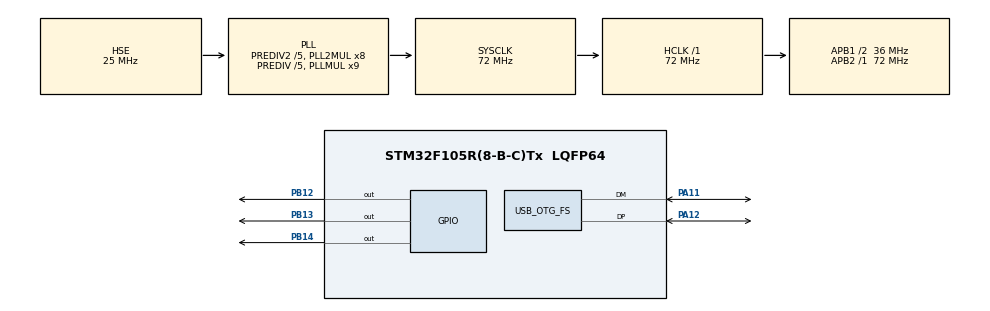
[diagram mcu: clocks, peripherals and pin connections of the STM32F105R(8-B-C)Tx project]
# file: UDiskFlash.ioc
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Mcu.Family=STM32F1
Mcu.Name=STM32F105R(8-B-C)Tx
Mcu.Package=LQFP64
NVIC.OTG_FS_IRQn=true\:1\:0\:true\:false\:true\:true\:true
NVIC.PriorityGroup=NVIC_PRIORITYGROUP_4
PA11.Mode=Device_Only
PA11.Signal=USB_OTG_FS_DM
PA12.Mode=Device_Only
PA12.Signal=USB_OTG_FS_DP
PB12.Signal=GPIO_Output
PB13.Signal=GPIO_Output
PB14.Signal=GPIO_Output
PD0-OSC_IN.Mode=HSE-External-Oscillator
PD0-OSC_IN.Signal=RCC_OSC_IN
PD1-OSC_OUT.Mode=HSE-External-Oscillator
PD1-OSC_OUT.Signal=RCC_OSC_OUT
ProjectManager.HeapSize=0x800
ProjectManager.StackSize=0x1000
ProjectManager.TargetToolchain=MDK-ARM V5
RCC.AHBFreq_Value=72000000
RCC.APB1CLKDivider=RCC_HCLK_DIV2
RCC.APB1Freq_Value=36000000
RCC.APB1TimFreq_Value=72000000
RCC.APB2Freq_Value=72000000
RCC.APB2TimFreq_Value=72000000
RCC.HCLKFreq_Value=72000000
RCC.HSEDivPLL=RCC_HSE_PREDIV_DIV5
RCC.HSE_VALUE=25000000
RCC.PLLMUL=RCC_PLL_MUL9
RCC.Prediv1Source=RCC_PREDIV1_SOURCE_PLL2
RCC.Prediv2=RCC_HSE_PREDIV2_DIV5
RCC.SYSCLKFreq_VALUE=72000000
RCC.SYSCLKSource=RCC_SYSCLKSOURCE_PLLCLK
RCC.USBFreq_Value=48000000
USB_DEVICE.CLASS_NAME_FS=MSC
USB_DEVICE.MANUFACTURER_STRING=ShareLink
USB_DEVICE.PRODUCT_STRING_MSC_FS=XL Mass Storage
USB_DEVICE.VirtualMode=Msc
USB_DEVICE.VirtualModeFS=Msc_FS
USB_OTG_FS.VirtualMode=Device_Only
VP_SYS_VS_ND.Mode=No_Debug
VP_USB_DEVICE_VS_USB_DEVICE_MSC_FS.Mode=MSC_FS
board=custom

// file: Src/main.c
/* USER CODE BEGIN Header */
/**
  ******************************************************************************
  * @file           : main.c
  * @brief          : Main program body
  ******************************************************************************
  * @attention
  *
  * <h2><center>&copy; Copyright (c) 2019 STMicroelectronics.
  * All rights reserved.</center></h2>
  *
  * This software component is licensed by ST under Ultimate Liberty license
  * SLA0044, the "License"; You may not use this file except in compliance with
  * the License. You may obtain a copy of the License at:
  *                             www.st.com/SLA0044
  *
  ******************************************************************************
  */
/* USER CODE END Header */

#include "main.h"
#include "usb_device.h"

/* USER CODE BEGIN PV */
typedef  void (*pFunction)(void);
uint32_t JumpAddress;
pFunction Jump_To_Application;

/* USER CODE END PV */

void SystemClock_Config(void);
static void MX_GPIO_Init(void);

int main(void)
{
	/* USER CODE BEGIN 1 */
	uint32_t i=0;

  /* USER CODE END 1 */

  /* MCU Configuration--------------------------------------------------------*/
  /* Reset of all peripherals, Initializes the Flash interface and the Systick. */
  HAL_Init();
  /* Configure the system clock */
  SystemClock_Config();
  /* USER CODE BEGIN SysInit */
	MX_GPIO_Init();
	/* USER CODE END SysInit */
	if(!HAL_GPIO_ReadPin(GPIOB, GPIO_PIN_4)){
		HAL_GPIO_WritePin(GPIOB, GPIO_PIN_12,GPIO_PIN_RESET);	//SYS_LED_ON
		/* Initialize all configured peripherals */
		MX_USB_DEVICE_Init();
		while(1);
	}

	/* USER CODE BEGIN 2 */
	__set_PRIMASK(1);
	if(((*(__IO uint32_t *) ApplicationAddress) & 0x2FFE0000) == 0x20000000)
	{
    HAL_DeInit();
		JumpAddress = *(__IO uint32_t *) (ApplicationAddress + 4);
		Jump_To_Application = (pFunction) JumpAddress;

		__set_MSP(*(__IO uint32_t *) ApplicationAddress);
		Jump_To_Application();
	}

  /* USER CODE END 2 */

  /* Infinite loop */
  while (1)
  {
		Error_Handler();
  }
}

void SystemClock_Config(void)
{
  RCC_OscInitTypeDef RCC_OscInitStruct = {0};
  RCC_ClkInitTypeDef RCC_ClkInitStruct = {0};
  RCC_PeriphCLKInitTypeDef PeriphClkInit = {0};

  /** Initializes the CPU, AHB and APB busses clocks
  */
  RCC_OscInitStruct.OscillatorType = RCC_OSCILLATORTYPE_HSE;
  RCC_OscInitStruct.HSEState = RCC_HSE_ON;
  RCC_OscInitStruct.HSEPredivValue = RCC_HSE_PREDIV_DIV5;
  RCC_OscInitStruct.HSIState = RCC_HSI_ON;
  RCC_OscInitStruct.Prediv1Source = RCC_PREDIV1_SOURCE_PLL2;
  RCC_OscInitStruct.PLL.PLLState = RCC_PLL_ON;
  RCC_OscInitStruct.PLL.PLLSource = RCC_PLLSOURCE_HSE;
  RCC_OscInitStruct.PLL.PLLMUL = RCC_PLL_MUL9;
  RCC_OscInitStruct.PLL2.PLL2State = RCC_PLL2_ON;
  RCC_OscInitStruct.PLL2.PLL2MUL = RCC_PLL2_MUL8;
  RCC_OscInitStruct.PLL2.HSEPrediv2Value = RCC_HSE_PREDIV2_DIV5;
  if (HAL_RCC_OscConfig(&RCC_OscInitStruct) != HAL_OK)
  {
    Error_Handler();
  }
  /** Initializes the CPU, AHB and APB busses clocks
  */
  RCC_ClkInitStruct.ClockType = RCC_CLOCKTYPE_HCLK|RCC_CLOCKTYPE_SYSCLK
                              |RCC_CLOCKTYPE_PCLK1|RCC_CLOCKTYPE_PCLK2;
  RCC_ClkInitStruct.SYSCLKSource = RCC_SYSCLKSOURCE_PLLCLK;
  RCC_ClkInitStruct.AHBCLKDivider = RCC_SYSCLK_DIV1;
  RCC_ClkInitStruct.APB1CLKDivider = RCC_HCLK_DIV2;
  RCC_ClkInitStruct.APB2CLKDivider = RCC_HCLK_DIV1;

  if (HAL_RCC_ClockConfig(&RCC_ClkInitStruct, FLASH_LATENCY_2) != HAL_OK)
  {
    Error_Handler();
  }
  PeriphClkInit.PeriphClockSelection = RCC_PERIPHCLK_USB;
  PeriphClkInit.UsbClockSelection = RCC_USBCLKSOURCE_PLL_DIV3;
  if (HAL_RCCEx_PeriphCLKConfig(&PeriphClkInit) != HAL_OK)
  {
    Error_Handler();
  }
  /** Configure the Systick interrupt time
  */
  __HAL_RCC_PLLI2S_ENABLE();
}

static void MX_GPIO_Init(void)
{
  GPIO_InitTypeDef GPIO_InitStruct = {0};

  /* GPIO Ports Clock Enable */
  __HAL_RCC_GPIOD_CLK_ENABLE();
  __HAL_RCC_GPIOB_CLK_ENABLE();
  __HAL_RCC_GPIOA_CLK_ENABLE();

  /*Configure GPIO pin Output Level */
  HAL_GPIO_WritePin(GPIOB, GPIO_PIN_12|GPIO_PIN_13|GPIO_PIN_14, GPIO_PIN_RESET);

  /*Configure GPIO pins : PB12 PB13 PB14 */
  GPIO_InitStruct.Pin = GPIO_PIN_12|GPIO_PIN_13|GPIO_PIN_14;
  GPIO_InitStruct.Mode = GPIO_MODE_OUTPUT_PP;
  GPIO_InitStruct.Pull = GPIO_NOPULL;
  GPIO_InitStruct.Speed = GPIO_SPEED_FREQ_LOW;
  HAL_GPIO_Init(GPIOB, &GPIO_InitStruct);

	HAL_GPIO_WritePin(GPIOB, GPIO_PIN_13,GPIO_PIN_SET);	//CAN1_LED
	HAL_GPIO_WritePin(GPIOB, GPIO_PIN_14,GPIO_PIN_SET); //CAN2_LED

	GPIO_InitStruct.Pin = GPIO_PIN_3;
	GPIO_InitStruct.Mode = GPIO_MODE_OUTPUT_OD;
  GPIO_InitStruct.Pull = GPIO_NOPULL;
	GPIO_InitStruct.Speed = GPIO_SPEED_FREQ_LOW;
	HAL_GPIO_Init(GPIOB, &GPIO_InitStruct);
	HAL_GPIO_WritePin(GPIOB, GPIO_PIN_3,GPIO_PIN_SET);	//High level

	GPIO_InitStruct.Pin = GPIO_PIN_4;
	GPIO_InitStruct.Mode = GPIO_MODE_INPUT;
  GPIO_InitStruct.Pull = GPIO_NOPULL;
	GPIO_InitStruct.Speed = GPIO_SPEED_FREQ_LOW;
	HAL_GPIO_Init(GPIOB, &GPIO_InitStruct);							//Wait for external pull down

}

void Error_Handler(void)
{
  /* USER CODE BEGIN Error_Handler_Debug */
  /* User can add his own implementation to report the HAL error return state */
	HAL_GPIO_WritePin(GPIOB, GPIO_PIN_12,GPIO_PIN_SET);	//SYS_LED
	while(1);
  /* USER CODE END Error_Handler_Debug */
}

/************************ (C) COPYRIGHT STMicroelectronics *****END OF FILE****/
